VERSION 5.7 ;
  NOWIREEXTENSIONATPIN ON ;
  DIVIDERCHAR "/" ;
  BUSBITCHARS "[]" ;
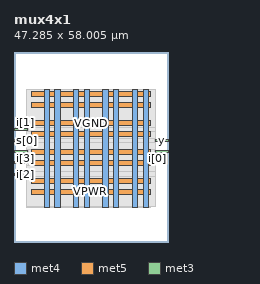
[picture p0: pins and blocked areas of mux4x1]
MACRO mux4x1
  CLASS BLOCK ;
  FOREIGN mux4x1 ;
  ORIGIN 0.000 0.000 ;
  SIZE 47.285 BY 58.005 ;
  PIN VGND
    DIRECTION INOUT ;
    USE GROUND ;
    PORT
      LAYER met4 ;
        RECT 12.500 10.640 14.100 46.480 ;
    END
    PORT
      LAYER met4 ;
        RECT 21.465 10.640 23.065 46.480 ;
    END
    PORT
      LAYER met4 ;
        RECT 30.430 10.640 32.030 46.480 ;
    END
    PORT
      LAYER met4 ;
        RECT 39.395 10.640 40.995 46.480 ;
    END
    PORT
      LAYER met5 ;
        RECT 5.280 17.800 41.640 19.400 ;
    END
    PORT
      LAYER met5 ;
        RECT 5.280 26.640 41.640 28.240 ;
    END
    PORT
      LAYER met5 ;
        RECT 5.280 35.480 41.640 37.080 ;
    END
    PORT
      LAYER met5 ;
        RECT 5.280 44.320 41.640 45.920 ;
    END
  END VGND
  PIN VPWR
    DIRECTION INOUT ;
    USE POWER ;
    PORT
      LAYER met4 ;
        RECT 9.200 10.640 10.800 46.480 ;
    END
    PORT
      LAYER met4 ;
        RECT 18.165 10.640 19.765 46.480 ;
    END
    PORT
      LAYER met4 ;
        RECT 27.130 10.640 28.730 46.480 ;
    END
    PORT
      LAYER met4 ;
        RECT 36.095 10.640 37.695 46.480 ;
    END
    PORT
      LAYER met5 ;
        RECT 5.280 14.500 41.640 16.100 ;
    END
    PORT
      LAYER met5 ;
        RECT 5.280 23.340 41.640 24.940 ;
    END
    PORT
      LAYER met5 ;
        RECT 5.280 32.180 41.640 33.780 ;
    END
    PORT
      LAYER met5 ;
        RECT 5.280 41.020 41.640 42.620 ;
    END
  END VPWR
  PIN i[0]
    DIRECTION INPUT ;
    USE SIGNAL ;
    ANTENNAGATEAREA 0.196500 ;
    PORT
      LAYER met3 ;
        RECT 43.285 27.240 47.285 27.840 ;
    END
  END i[0]
  PIN i[1]
    DIRECTION INPUT ;
    USE SIGNAL ;
    ANTENNAGATEAREA 0.196500 ;
    PORT
      LAYER met3 ;
        RECT 0.000 34.040 4.000 34.640 ;
    END
  END i[1]
  PIN i[2]
    DIRECTION INPUT ;
    USE SIGNAL ;
    ANTENNAGATEAREA 0.196500 ;
    PORT
      LAYER met3 ;
        RECT 0.000 20.440 4.000 21.040 ;
    END
  END i[2]
  PIN i[3]
    DIRECTION INPUT ;
    USE SIGNAL ;
    ANTENNAGATEAREA 0.196500 ;
    PORT
      LAYER met3 ;
        RECT 0.000 27.240 4.000 27.840 ;
    END
  END i[3]
  PIN s[0]
    DIRECTION INPUT ;
    USE SIGNAL ;
    ANTENNAGATEAREA 0.196500 ;
    PORT
      LAYER met3 ;
        RECT 0.000 30.640 4.000 31.240 ;
    END
  END s[0]
  PIN s[1]
    DIRECTION INPUT ;
    USE SIGNAL ;
    ANTENNAGATEAREA 0.196500 ;
    PORT
      LAYER met3 ;
        RECT 0.000 23.840 4.000 24.440 ;
    END
  END s[1]
  PIN y
    DIRECTION OUTPUT TRISTATE ;
    USE SIGNAL ;
    ANTENNADIFFAREA 0.445500 ;
    PORT
      LAYER met3 ;
        RECT 43.285 30.640 47.285 31.240 ;
    END
  END y
  OBS
      LAYER li1 ;
        RECT 5.520 10.795 41.400 46.325 ;
      LAYER met1 ;
        RECT 3.750 10.640 41.790 46.480 ;
      LAYER met2 ;
        RECT 3.770 10.695 41.770 46.425 ;
      LAYER met3 ;
        RECT 3.745 35.040 43.285 46.405 ;
        RECT 4.400 33.640 43.285 35.040 ;
        RECT 3.745 31.640 43.285 33.640 ;
        RECT 4.400 30.240 42.885 31.640 ;
        RECT 3.745 28.240 43.285 30.240 ;
        RECT 4.400 26.840 42.885 28.240 ;
        RECT 3.745 24.840 43.285 26.840 ;
        RECT 4.400 23.440 43.285 24.840 ;
        RECT 3.745 21.440 43.285 23.440 ;
        RECT 4.400 20.040 43.285 21.440 ;
        RECT 3.745 10.715 43.285 20.040 ;
  END
END mux4x1
END LIBRARY

